VERSION 5.8 ;
BUSBITCHARS "[]" ;
DIVIDERCHAR "/" ;
UNITS
    DATABASE MICRONS 1000 ;
END UNITS

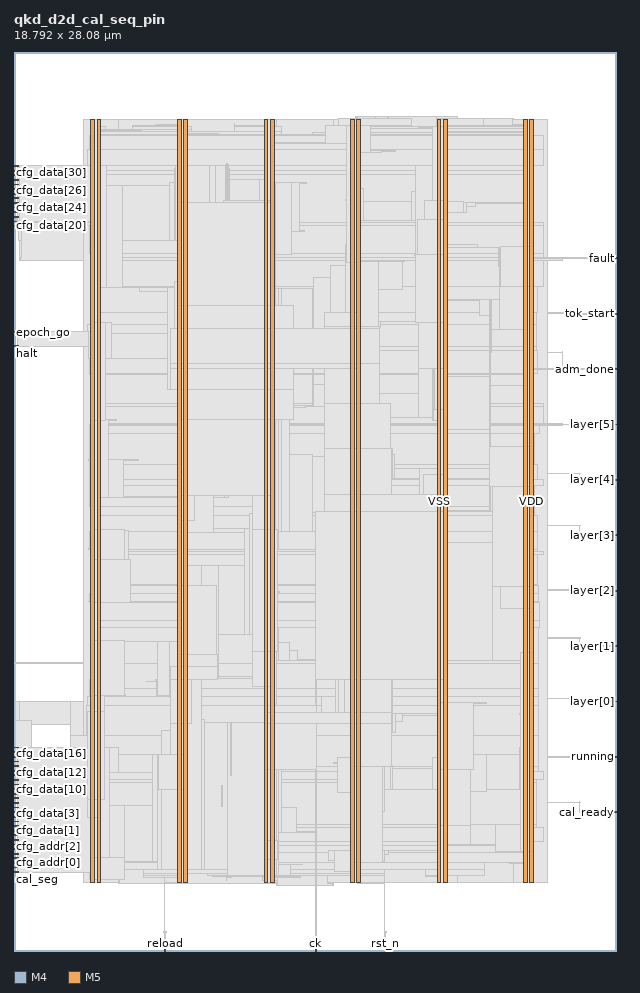
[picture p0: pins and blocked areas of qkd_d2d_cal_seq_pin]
MACRO qkd_d2d_cal_seq_pin
  FOREIGN qkd_d2d_cal_seq_pin 0 0 ;
  CLASS BLOCK ;
  SIZE 18.792 BY 28.08 ;
  PIN adm_done
    DIRECTION OUTPUT ;
    USE SIGNAL ;
    PORT
      LAYER M4 ;
        RECT  18.648 18.144 18.792 18.168 ;
    END
  END adm_done
  PIN cal_ready
    DIRECTION OUTPUT ;
    USE SIGNAL ;
    PORT
      LAYER M4 ;
        RECT  18.648 4.32 18.792 4.344 ;
    END
  END cal_ready
  PIN cal_seg
    DIRECTION OUTPUT ;
    USE SIGNAL ;
    PORT
      LAYER M4 ;
        RECT  0 2.448 0.144 2.472 ;
    END
  END cal_seg
  PIN cal_start
    DIRECTION OUTPUT ;
    USE SIGNAL ;
    PORT
      LAYER M4 ;
        RECT  0 2.592 0.144 2.616 ;
    END
  END cal_start
  PIN cfg_addr[0]
    DIRECTION OUTPUT ;
    USE SIGNAL ;
    PORT
      LAYER M4 ;
        RECT  0 2.736 0.144 2.76 ;
    END
  END cfg_addr[0]
  PIN cfg_addr[1]
    DIRECTION OUTPUT ;
    USE SIGNAL ;
    PORT
      LAYER M4 ;
        RECT  0 2.88 0.144 2.904 ;
    END
  END cfg_addr[1]
  PIN cfg_addr[2]
    DIRECTION OUTPUT ;
    USE SIGNAL ;
    PORT
      LAYER M4 ;
        RECT  0 3.024 0.144 3.048 ;
    END
  END cfg_addr[2]
  PIN cfg_addr[3]
    DIRECTION OUTPUT ;
    USE SIGNAL ;
    PORT
      LAYER M4 ;
        RECT  0 3.168 0.144 3.192 ;
    END
  END cfg_addr[3]
  PIN cfg_addr[4]
    DIRECTION OUTPUT ;
    USE SIGNAL ;
    PORT
      LAYER M4 ;
        RECT  0 3.312 0.144 3.336 ;
    END
  END cfg_addr[4]
  PIN cfg_addr[5]
    DIRECTION OUTPUT ;
    USE SIGNAL ;
    PORT
      LAYER M4 ;
        RECT  0 3.456 0.144 3.48 ;
    END
  END cfg_addr[5]
  PIN cfg_data[0]
    DIRECTION OUTPUT ;
    USE SIGNAL ;
    PORT
      LAYER M4 ;
        RECT  0 3.6 0.144 3.624 ;
    END
  END cfg_data[0]
  PIN cfg_data[10]
    DIRECTION OUTPUT ;
    USE SIGNAL ;
    PORT
      LAYER M4 ;
        RECT  0 5.04 0.144 5.064 ;
    END
  END cfg_data[10]
  PIN cfg_data[11]
    DIRECTION OUTPUT ;
    USE SIGNAL ;
    PORT
      LAYER M4 ;
        RECT  0 5.184 0.144 5.208 ;
    END
  END cfg_data[11]
  PIN cfg_data[12]
    DIRECTION OUTPUT ;
    USE SIGNAL ;
    PORT
      LAYER M4 ;
        RECT  0 5.328 0.144 5.352 ;
    END
  END cfg_data[12]
  PIN cfg_data[13]
    DIRECTION OUTPUT ;
    USE SIGNAL ;
    PORT
      LAYER M4 ;
        RECT  0 5.472 0.144 5.496 ;
    END
  END cfg_data[13]
  PIN cfg_data[14]
    DIRECTION OUTPUT ;
    USE SIGNAL ;
    PORT
      LAYER M4 ;
        RECT  0 5.616 0.144 5.64 ;
    END
  END cfg_data[14]
  PIN cfg_data[15]
    DIRECTION OUTPUT ;
    USE SIGNAL ;
    PORT
      LAYER M4 ;
        RECT  0 5.76 0.144 5.784 ;
    END
  END cfg_data[15]
  PIN cfg_data[16]
    DIRECTION OUTPUT ;
    USE SIGNAL ;
    PORT
      LAYER M4 ;
        RECT  0 5.904 0.144 5.928 ;
    END
  END cfg_data[16]
  PIN cfg_data[17]
    DIRECTION OUTPUT ;
    USE SIGNAL ;
    PORT
      LAYER M4 ;
        RECT  0 6.048 0.144 6.072 ;
    END
  END cfg_data[17]
  PIN cfg_data[18]
    DIRECTION OUTPUT ;
    USE SIGNAL ;
    PORT
      LAYER M4 ;
        RECT  0 6.192 0.144 6.216 ;
    END
  END cfg_data[18]
  PIN cfg_data[19]
    DIRECTION OUTPUT ;
    USE SIGNAL ;
    PORT
      LAYER M4 ;
        RECT  0 6.336 0.144 6.36 ;
    END
  END cfg_data[19]
  PIN cfg_data[1]
    DIRECTION OUTPUT ;
    USE SIGNAL ;
    PORT
      LAYER M4 ;
        RECT  0 3.744 0.144 3.768 ;
    END
  END cfg_data[1]
  PIN cfg_data[20]
    DIRECTION OUTPUT ;
    USE SIGNAL ;
    PORT
      LAYER M4 ;
        RECT  0 22.608 0.144 22.632 ;
    END
  END cfg_data[20]
  PIN cfg_data[21]
    DIRECTION OUTPUT ;
    USE SIGNAL ;
    PORT
      LAYER M4 ;
        RECT  0 22.752 0.144 22.776 ;
    END
  END cfg_data[21]
  PIN cfg_data[22]
    DIRECTION OUTPUT ;
    USE SIGNAL ;
    PORT
      LAYER M4 ;
        RECT  0 22.896 0.144 22.92 ;
    END
  END cfg_data[22]
  PIN cfg_data[23]
    DIRECTION OUTPUT ;
    USE SIGNAL ;
    PORT
      LAYER M4 ;
        RECT  0 23.04 0.144 23.064 ;
    END
  END cfg_data[23]
  PIN cfg_data[24]
    DIRECTION OUTPUT ;
    USE SIGNAL ;
    PORT
      LAYER M4 ;
        RECT  0 23.184 0.144 23.208 ;
    END
  END cfg_data[24]
  PIN cfg_data[25]
    DIRECTION OUTPUT ;
    USE SIGNAL ;
    PORT
      LAYER M4 ;
        RECT  0 23.328 0.144 23.352 ;
    END
  END cfg_data[25]
  PIN cfg_data[26]
    DIRECTION OUTPUT ;
    USE SIGNAL ;
    PORT
      LAYER M4 ;
        RECT  0 23.472 0.144 23.496 ;
    END
  END cfg_data[26]
  PIN cfg_data[27]
    DIRECTION OUTPUT ;
    USE SIGNAL ;
    PORT
      LAYER M4 ;
        RECT  0 23.616 0.144 23.64 ;
    END
  END cfg_data[27]
  PIN cfg_data[28]
    DIRECTION OUTPUT ;
    USE SIGNAL ;
    PORT
      LAYER M4 ;
        RECT  0 23.76 0.144 23.784 ;
    END
  END cfg_data[28]
  PIN cfg_data[29]
    DIRECTION OUTPUT ;
    USE SIGNAL ;
    PORT
      LAYER M4 ;
        RECT  0 23.904 0.144 23.928 ;
    END
  END cfg_data[29]
  PIN cfg_data[2]
    DIRECTION OUTPUT ;
    USE SIGNAL ;
    PORT
      LAYER M4 ;
        RECT  0 3.888 0.144 3.912 ;
    END
  END cfg_data[2]
  PIN cfg_data[30]
    DIRECTION OUTPUT ;
    USE SIGNAL ;
    PORT
      LAYER M4 ;
        RECT  0 24.048 0.144 24.072 ;
    END
  END cfg_data[30]
  PIN cfg_data[31]
    DIRECTION OUTPUT ;
    USE SIGNAL ;
    PORT
      LAYER M4 ;
        RECT  0 24.192 0.144 24.216 ;
    END
  END cfg_data[31]
  PIN cfg_data[3]
    DIRECTION OUTPUT ;
    USE SIGNAL ;
    PORT
      LAYER M4 ;
        RECT  0 4.032 0.144 4.056 ;
    END
  END cfg_data[3]
  PIN cfg_data[4]
    DIRECTION OUTPUT ;
    USE SIGNAL ;
    PORT
      LAYER M4 ;
        RECT  0 4.176 0.144 4.2 ;
    END
  END cfg_data[4]
  PIN cfg_data[5]
    DIRECTION OUTPUT ;
    USE SIGNAL ;
    PORT
      LAYER M4 ;
        RECT  0 4.32 0.144 4.344 ;
    END
  END cfg_data[5]
  PIN cfg_data[6]
    DIRECTION OUTPUT ;
    USE SIGNAL ;
    PORT
      LAYER M4 ;
        RECT  0 4.464 0.144 4.488 ;
    END
  END cfg_data[6]
  PIN cfg_data[7]
    DIRECTION OUTPUT ;
    USE SIGNAL ;
    PORT
      LAYER M4 ;
        RECT  0 4.608 0.144 4.632 ;
    END
  END cfg_data[7]
  PIN cfg_data[8]
    DIRECTION OUTPUT ;
    USE SIGNAL ;
    PORT
      LAYER M4 ;
        RECT  0 4.752 0.144 4.776 ;
    END
  END cfg_data[8]
  PIN cfg_data[9]
    DIRECTION OUTPUT ;
    USE SIGNAL ;
    PORT
      LAYER M4 ;
        RECT  0 4.896 0.144 4.92 ;
    END
  END cfg_data[9]
  PIN cfg_rx_we
    DIRECTION OUTPUT ;
    USE SIGNAL ;
    PORT
      LAYER M4 ;
        RECT  0 24.336 0.144 24.36 ;
    END
  END cfg_rx_we
  PIN cfg_tx_we
    DIRECTION OUTPUT ;
    USE SIGNAL ;
    PORT
      LAYER M4 ;
        RECT  0 24.48 0.144 24.504 ;
    END
  END cfg_tx_we
  PIN ck
    DIRECTION INPUT ;
    USE SIGNAL ;
    PORT
      LAYER M5 ;
        RECT  9.408 0 9.432 0.144 ;
    END
  END ck
  PIN epoch_go
    DIRECTION INPUT ;
    USE SIGNAL ;
    PORT
      LAYER M4 ;
        RECT  0 19.296 0.144 19.32 ;
    END
  END epoch_go
  PIN fault
    DIRECTION OUTPUT ;
    USE SIGNAL ;
    PORT
      LAYER M4 ;
        RECT  18.648 21.6 18.792 21.624 ;
    END
  END fault
  PIN halt
    DIRECTION INPUT ;
    USE SIGNAL ;
    PORT
      LAYER M4 ;
        RECT  0 18.864 0.144 18.888 ;
    END
  END halt
  PIN layer[0]
    DIRECTION OUTPUT ;
    USE SIGNAL ;
    PORT
      LAYER M4 ;
        RECT  18.648 7.776 18.792 7.8 ;
    END
  END layer[0]
  PIN layer[1]
    DIRECTION OUTPUT ;
    USE SIGNAL ;
    PORT
      LAYER M4 ;
        RECT  18.648 9.504 18.792 9.528 ;
    END
  END layer[1]
  PIN layer[2]
    DIRECTION OUTPUT ;
    USE SIGNAL ;
    PORT
      LAYER M4 ;
        RECT  18.648 11.232 18.792 11.256 ;
    END
  END layer[2]
  PIN layer[3]
    DIRECTION OUTPUT ;
    USE SIGNAL ;
    PORT
      LAYER M4 ;
        RECT  18.648 12.96 18.792 12.984 ;
    END
  END layer[3]
  PIN layer[4]
    DIRECTION OUTPUT ;
    USE SIGNAL ;
    PORT
      LAYER M4 ;
        RECT  18.648 14.688 18.792 14.712 ;
    END
  END layer[4]
  PIN layer[5]
    DIRECTION OUTPUT ;
    USE SIGNAL ;
    PORT
      LAYER M4 ;
        RECT  18.648 16.416 18.792 16.44 ;
    END
  END layer[5]
  PIN reload
    DIRECTION INPUT ;
    USE SIGNAL ;
    PORT
      LAYER M5 ;
        RECT  4.704 0 4.728 0.144 ;
    END
  END reload
  PIN rst_n
    DIRECTION INPUT ;
    USE SIGNAL ;
    PORT
      LAYER M5 ;
        RECT  11.568 0 11.592 0.144 ;
    END
  END rst_n
  PIN running
    DIRECTION OUTPUT ;
    USE SIGNAL ;
    PORT
      LAYER M4 ;
        RECT  18.648 6.048 18.792 6.072 ;
    END
  END running
  PIN tok_start
    DIRECTION OUTPUT ;
    USE SIGNAL ;
    PORT
      LAYER M4 ;
        RECT  18.648 19.872 18.792 19.896 ;
    END
  END tok_start
  PIN VDD
    DIRECTION INOUT ;
    USE POWER ;
    PORT
      LAYER M5 ;
        RECT  16.092 2.151 16.212 25.929 ;
        RECT  13.392 2.151 13.512 25.929 ;
        RECT  10.692 2.151 10.812 25.929 ;
        RECT  7.992 2.151 8.112 25.929 ;
        RECT  5.292 2.151 5.412 25.929 ;
        RECT  2.592 2.151 2.712 25.929 ;
    END
  END VDD
  PIN VSS
    DIRECTION INOUT ;
    USE GROUND ;
    PORT
      LAYER M5 ;
        RECT  15.9 2.137 16.02 25.943 ;
        RECT  13.2 2.137 13.32 25.943 ;
        RECT  10.5 2.137 10.62 25.943 ;
        RECT  7.8 2.137 7.92 25.943 ;
        RECT  5.1 2.137 5.22 25.943 ;
        RECT  2.4 2.137 2.52 25.943 ;
    END
  END VSS
  OBS
    LAYER RVTN ;
     RECT  2.16 2.16 16.632 2.295 ;
     RECT  2.16 2.565 16.632 2.835 ;
     RECT  2.16 3.105 16.632 3.375 ;
     RECT  2.16 3.645 16.632 3.915 ;
     RECT  2.16 4.185 16.632 4.455 ;
     RECT  2.16 4.725 16.632 4.995 ;
     RECT  2.16 5.265 16.632 5.535 ;
     RECT  2.16 5.805 16.632 6.075 ;
     RECT  2.16 6.345 16.632 6.615 ;
     RECT  2.16 6.885 16.632 7.155 ;
     RECT  2.16 7.425 16.632 7.695 ;
     RECT  2.16 7.965 16.632 8.235 ;
     RECT  2.16 8.505 16.632 8.775 ;
     RECT  2.16 9.045 16.632 9.315 ;
     RECT  2.16 9.585 16.632 9.855 ;
     RECT  2.16 10.125 16.632 10.395 ;
     RECT  2.16 10.665 16.632 10.935 ;
     RECT  2.16 11.205 16.632 11.475 ;
     RECT  2.16 11.745 16.632 12.015 ;
     RECT  2.16 12.285 16.632 12.555 ;
     RECT  2.16 12.825 16.632 13.095 ;
     RECT  2.16 13.365 16.632 13.635 ;
     RECT  2.16 13.905 16.632 14.175 ;
     RECT  2.16 14.445 16.632 14.715 ;
     RECT  2.16 14.985 16.632 15.255 ;
     RECT  2.16 15.525 16.632 15.795 ;
     RECT  2.16 16.065 16.632 16.335 ;
     RECT  2.16 16.605 16.632 16.875 ;
     RECT  2.16 17.145 16.632 17.415 ;
     RECT  2.16 17.685 16.632 17.955 ;
     RECT  2.16 18.225 16.632 18.495 ;
     RECT  2.16 18.765 16.632 19.035 ;
     RECT  2.16 19.305 16.632 19.575 ;
     RECT  2.16 19.845 16.632 20.115 ;
     RECT  2.16 20.385 16.632 20.655 ;
     RECT  2.16 20.925 16.632 21.195 ;
     RECT  2.16 21.465 16.632 21.735 ;
     RECT  2.16 22.005 16.632 22.275 ;
     RECT  2.16 22.545 16.632 22.815 ;
     RECT  2.16 23.085 16.632 23.355 ;
     RECT  2.16 23.625 16.632 23.895 ;
     RECT  2.16 24.165 16.632 24.435 ;
     RECT  2.16 24.705 16.632 24.975 ;
     RECT  2.16 25.245 16.632 25.515 ;
     RECT  2.16 25.785 16.632 25.92 ;
    LAYER RVTP ;
     RECT  2.16 2.295 16.632 2.565 ;
     RECT  2.16 2.835 16.632 3.105 ;
     RECT  2.16 3.375 16.632 3.645 ;
     RECT  2.16 3.915 16.632 4.185 ;
     RECT  2.16 4.455 16.632 4.725 ;
     RECT  2.16 4.995 16.632 5.265 ;
     RECT  2.16 5.535 16.632 5.805 ;
     RECT  2.16 6.075 16.632 6.345 ;
     RECT  2.16 6.615 16.632 6.885 ;
     RECT  2.16 7.155 16.632 7.425 ;
     RECT  2.16 7.695 16.632 7.965 ;
     RECT  2.16 8.235 16.632 8.505 ;
     RECT  2.16 8.775 16.632 9.045 ;
     RECT  2.16 9.315 16.632 9.585 ;
     RECT  2.16 9.855 16.632 10.125 ;
     RECT  2.16 10.395 16.632 10.665 ;
     RECT  2.16 10.935 16.632 11.205 ;
     RECT  2.16 11.475 16.632 11.745 ;
     RECT  2.16 12.015 16.632 12.285 ;
     RECT  2.16 12.555 16.632 12.825 ;
     RECT  2.16 13.095 16.632 13.365 ;
     RECT  2.16 13.635 16.632 13.905 ;
     RECT  2.16 14.175 16.632 14.445 ;
     RECT  2.16 14.715 16.632 14.985 ;
     RECT  2.16 15.255 16.632 15.525 ;
     RECT  2.16 15.795 16.632 16.065 ;
     RECT  2.16 16.335 16.632 16.605 ;
     RECT  2.16 16.875 16.632 17.145 ;
     RECT  2.16 17.415 16.632 17.685 ;
     RECT  2.16 17.955 16.632 18.225 ;
     RECT  2.16 18.495 16.632 18.765 ;
     RECT  2.16 19.035 16.632 19.305 ;
     RECT  2.16 19.575 16.632 19.845 ;
     RECT  2.16 20.115 16.632 20.385 ;
     RECT  2.16 20.655 16.632 20.925 ;
     RECT  2.16 21.195 16.632 21.465 ;
     RECT  2.16 21.735 16.632 22.005 ;
     RECT  2.16 22.275 16.632 22.545 ;
     RECT  2.16 22.815 16.632 23.085 ;
     RECT  2.16 23.355 16.632 23.625 ;
     RECT  2.16 23.895 16.632 24.165 ;
     RECT  2.16 24.435 16.632 24.705 ;
     RECT  2.16 24.975 16.632 25.245 ;
     RECT  2.16 25.515 16.632 25.785 ;
    LAYER M1 ;
     RECT  2.16 2.151 16.632 25.929 ;
    LAYER M2 ;
     RECT  0.067 22.716 0.139 22.842 ;
     RECT  0.031 5.121 0.167 5.139 ;
     RECT  0.139 22.176 0.167 22.842 ;
     RECT  0.139 7.776 0.175 7.794 ;
     RECT  0.167 22.176 0.175 22.734 ;
     RECT  0.139 2.646 0.535 2.664 ;
     RECT  0.175 7.056 1.759 7.794 ;
     RECT  0.535 2.646 2.16 2.754 ;
     RECT  1.759 6.696 2.16 7.794 ;
     RECT  0.031 8.982 2.16 9 ;
     RECT  0.175 21.546 2.16 22.734 ;
     RECT  2.16 2.151 3.271 25.929 ;
     RECT  3.271 2.106 8.203 25.929 ;
     RECT  8.203 2.034 9.959 25.929 ;
     RECT  9.959 2.151 10.111 25.929 ;
     RECT  10.111 2.151 10.651 25.974 ;
     RECT  10.651 2.151 10.723 26.046 ;
     RECT  10.723 2.106 11.291 26.046 ;
     RECT  11.291 2.151 13.847 26.046 ;
     RECT  13.847 2.151 15.575 25.974 ;
     RECT  15.575 2.151 16.632 25.929 ;
     RECT  16.632 16.416 17.123 16.434 ;
     RECT  16.632 18.666 17.123 18.684 ;
     RECT  16.632 21.546 17.123 21.564 ;
     RECT  16.632 4.626 17.663 4.644 ;
     RECT  16.632 6.048 17.663 6.066 ;
     RECT  16.632 7.866 17.663 7.884 ;
     RECT  16.632 9.756 17.663 9.774 ;
     RECT  16.632 11.25 17.663 11.268 ;
     RECT  16.632 13.266 17.663 13.284 ;
     RECT  16.632 14.886 17.663 14.904 ;
     RECT  16.632 19.89 17.663 19.908 ;
    LAYER M3 ;
     RECT  9.936 2.029 9.954 2.101 ;
     RECT  11.556 0.571 11.574 2.101 ;
     RECT  4.68 0.571 4.698 2.143 ;
     RECT  8.208 2.029 8.226 2.143 ;
     RECT  9.792 2.101 9.954 2.143 ;
     RECT  10.728 2.101 11.574 2.143 ;
     RECT  7.815 2.143 8.226 2.191 ;
     RECT  2.415 2.143 2.505 2.227 ;
     RECT  2.34 2.227 2.505 2.251 ;
     RECT  3.276 2.101 3.294 2.251 ;
     RECT  4.68 2.143 5.205 2.299 ;
     RECT  6.624 2.191 6.642 2.299 ;
     RECT  7.74 2.191 8.226 2.299 ;
     RECT  6.624 2.299 6.786 2.335 ;
     RECT  7.74 2.299 8.946 2.335 ;
     RECT  13.215 2.143 13.305 2.335 ;
     RECT  4.032 2.299 5.205 2.371 ;
     RECT  6.192 2.335 8.946 2.371 ;
     RECT  9.792 2.143 11.574 2.371 ;
     RECT  12.852 2.335 13.305 2.371 ;
     RECT  4.032 2.371 5.274 2.413 ;
     RECT  6.048 2.371 11.574 2.413 ;
     RECT  15.915 2.143 16.005 2.413 ;
     RECT  2.34 2.251 3.294 2.443 ;
     RECT  2.304 2.443 3.294 2.533 ;
     RECT  4.032 2.413 11.574 2.533 ;
     RECT  12.852 2.371 14.67 2.533 ;
     RECT  0.144 2.641 0.162 2.731 ;
     RECT  15.915 2.413 16.197 2.731 ;
     RECT  2.304 2.533 14.67 2.767 ;
     RECT  15.444 2.731 16.197 2.767 ;
     RECT  0.144 2.731 0.558 2.909 ;
     RECT  0.144 2.909 0.162 3.053 ;
     RECT  2.304 2.767 16.197 3.073 ;
     RECT  2.268 3.073 16.197 3.299 ;
     RECT  2.304 3.299 16.197 3.415 ;
     RECT  2.304 3.415 16.506 3.839 ;
     RECT  2.304 3.839 16.29 3.947 ;
     RECT  0.216 4.027 0.234 4.445 ;
     RECT  17.64 4.315 17.658 4.649 ;
     RECT  0.18 4.603 0.198 4.891 ;
     RECT  0.144 4.891 0.198 5.116 ;
     RECT  2.34 3.947 16.29 5.269 ;
     RECT  0.036 5.116 0.198 5.323 ;
     RECT  2.304 5.269 16.29 5.341 ;
     RECT  2.304 5.341 16.506 5.603 ;
     RECT  2.304 5.603 16.362 5.755 ;
     RECT  0.036 5.323 0.378 6.043 ;
     RECT  17.64 6.043 17.658 6.08 ;
     RECT  1.764 5.755 16.362 6.719 ;
     RECT  0.036 6.043 0.558 7.187 ;
     RECT  2.268 6.719 16.362 7.655 ;
     RECT  0.036 7.187 0.162 7.799 ;
     RECT  17.64 7.771 17.658 7.889 ;
     RECT  2.304 7.655 16.362 7.925 ;
     RECT  2.34 7.925 16.362 8.195 ;
     RECT  2.34 8.195 2.697 8.465 ;
     RECT  2.415 8.465 2.697 8.971 ;
     RECT  3.42 8.195 16.362 8.971 ;
     RECT  0.036 7.799 0.054 9.005 ;
     RECT  17.64 9.499 17.658 9.779 ;
     RECT  2.415 8.971 16.362 10.093 ;
     RECT  2.415 10.093 16.398 10.327 ;
     RECT  2.376 10.327 16.398 10.859 ;
     RECT  2.376 10.859 16.362 10.891 ;
     RECT  2.34 10.891 16.362 11.165 ;
     RECT  17.64 11.227 17.658 11.273 ;
     RECT  2.376 11.165 16.362 11.399 ;
     RECT  2.376 11.399 16.326 11.435 ;
     RECT  2.415 11.435 16.326 12.361 ;
     RECT  2.415 12.361 16.506 12.479 ;
     RECT  2.415 12.479 16.326 12.523 ;
     RECT  2.34 12.523 16.326 13.091 ;
     RECT  17.64 12.955 17.658 13.289 ;
     RECT  2.376 13.091 16.326 13.595 ;
     RECT  2.376 13.595 16.254 13.873 ;
     RECT  2.34 13.873 16.254 14.521 ;
     RECT  2.34 14.521 16.506 14.711 ;
     RECT  17.64 14.683 17.658 14.909 ;
     RECT  2.34 14.711 16.326 15.179 ;
     RECT  2.34 15.179 16.254 16.141 ;
     RECT  2.34 16.141 16.398 16.405 ;
     RECT  2.34 16.405 17.118 16.439 ;
     RECT  2.376 16.439 17.118 16.445 ;
     RECT  2.376 16.445 16.506 16.979 ;
     RECT  2.415 16.979 16.506 17.069 ;
     RECT  2.415 17.069 16.197 17.995 ;
     RECT  2.34 17.995 16.197 18.031 ;
     RECT  17.1 18.139 17.118 18.689 ;
     RECT  2.34 18.031 16.326 18.725 ;
     RECT  2.34 18.725 16.29 18.859 ;
     RECT  2.304 18.859 16.29 19.535 ;
     RECT  17.64 19.867 17.658 19.913 ;
     RECT  2.415 19.535 16.29 19.921 ;
     RECT  2.415 19.921 16.326 20.731 ;
     RECT  2.415 20.731 16.506 21.541 ;
     RECT  2.415 21.541 17.118 21.629 ;
     RECT  0.18 21.541 0.198 21.631 ;
     RECT  2.415 21.629 16.506 21.775 ;
     RECT  0.18 21.631 0.234 22.171 ;
     RECT  0.144 22.171 0.234 22.549 ;
     RECT  2.34 21.775 16.506 22.621 ;
     RECT  0.144 22.549 0.27 22.711 ;
     RECT  2.304 22.621 16.506 22.739 ;
     RECT  0.072 22.711 0.27 22.847 ;
     RECT  0.144 22.847 0.27 23.083 ;
     RECT  0.144 23.083 0.306 23.213 ;
     RECT  0.144 23.213 0.27 23.357 ;
     RECT  0.144 23.357 0.234 23.885 ;
     RECT  0.144 23.885 0.162 24.077 ;
     RECT  2.304 22.739 16.197 24.241 ;
     RECT  2.268 24.241 16.197 24.365 ;
     RECT  2.304 24.365 16.197 24.511 ;
     RECT  2.304 24.511 16.506 25.007 ;
     RECT  2.34 25.007 16.506 25.439 ;
     RECT  2.415 25.439 16.197 25.475 ;
     RECT  9.324 25.475 16.197 25.547 ;
     RECT  2.415 25.475 8.334 25.583 ;
     RECT  2.415 25.583 5.526 25.619 ;
     RECT  9.72 25.547 16.197 25.667 ;
     RECT  2.415 25.619 2.862 25.709 ;
     RECT  3.708 25.619 5.526 25.709 ;
     RECT  6.876 25.583 8.334 25.709 ;
     RECT  9.72 25.667 16.074 25.715 ;
     RECT  3.708 25.709 5.205 25.745 ;
     RECT  6.876 25.709 7.905 25.745 ;
     RECT  13.176 25.715 16.074 25.745 ;
     RECT  9.72 25.715 12.402 25.757 ;
     RECT  4.428 25.745 5.205 25.781 ;
     RECT  15.552 25.745 16.074 25.781 ;
     RECT  6.876 25.745 6.894 25.817 ;
     RECT  2.415 25.709 2.682 25.889 ;
     RECT  2.415 25.889 2.505 25.937 ;
     RECT  5.115 25.781 5.205 25.937 ;
     RECT  7.815 25.745 7.905 25.937 ;
     RECT  15.552 25.781 16.005 25.937 ;
     RECT  10.116 25.757 12.402 25.979 ;
     RECT  13.176 25.745 14.634 25.979 ;
     RECT  15.552 25.937 15.57 25.979 ;
     RECT  10.656 25.979 10.674 26.051 ;
     RECT  11.664 25.979 11.682 26.051 ;
     RECT  13.176 25.979 13.842 26.051 ;
    LAYER M4 ;
     RECT  0.108 22.608 0.173 24.504 ;
     RECT  0.108 18.864 2.329 19.32 ;
     RECT  0.108 2.448 2.408 6.36 ;
     RECT  2.293 7.44 2.408 7.464 ;
     RECT  2.329 10.896 2.408 10.92 ;
     RECT  2.329 12.528 2.408 12.552 ;
     RECT  2.329 15.312 2.408 15.336 ;
     RECT  2.401 16.56 2.408 16.584 ;
     RECT  2.329 18.48 2.408 19.32 ;
     RECT  0.173 22.752 2.408 24.504 ;
     RECT  2.408 2.148 2.512 25.932 ;
     RECT  2.512 2.256 2.704 25.662 ;
     RECT  2.704 20.688 2.873 24.504 ;
     RECT  2.704 14.16 2.945 16.584 ;
     RECT  2.704 2.256 2.981 6.36 ;
     RECT  2.704 18.48 3.053 19.608 ;
     RECT  2.945 16.56 3.197 16.584 ;
     RECT  2.981 5.568 3.269 6.36 ;
     RECT  2.873 20.688 3.377 23.88 ;
     RECT  2.945 14.16 3.413 15.336 ;
     RECT  2.981 2.256 3.443 4.536 ;
     RECT  2.704 8.976 3.443 9.672 ;
     RECT  2.704 7.968 3.485 7.992 ;
     RECT  2.704 12.192 3.557 13.128 ;
     RECT  3.557 12.192 3.635 12.216 ;
     RECT  2.704 10.896 3.657 10.92 ;
     RECT  3.413 15.312 3.881 15.336 ;
     RECT  3.377 20.688 3.913 20.712 ;
     RECT  2.704 25.584 3.989 25.608 ;
     RECT  3.443 2.784 4.309 4.536 ;
     RECT  3.269 5.568 4.309 6.12 ;
     RECT  4.129 8.4 4.417 8.424 ;
     RECT  4.417 8.4 4.453 8.472 ;
     RECT  4.309 2.784 4.489 6.12 ;
     RECT  4.453 7.968 4.489 8.472 ;
     RECT  3.443 9.648 4.489 9.672 ;
     RECT  4.489 2.544 4.597 6.12 ;
     RECT  4.669 0.576 4.753 0.6 ;
     RECT  3.053 18.48 4.777 19.272 ;
     RECT  3.913 20.592 4.777 20.712 ;
     RECT  4.489 7.968 4.844 9.672 ;
     RECT  3.377 22.176 4.849 23.88 ;
     RECT  4.777 17.52 4.993 20.712 ;
     RECT  4.849 22.176 4.993 23.976 ;
     RECT  4.993 22.176 5.029 24.408 ;
     RECT  4.844 7.92 5.101 9.672 ;
     RECT  4.597 2.544 5.108 6.888 ;
     RECT  5.101 7.92 5.108 9.816 ;
     RECT  3.413 14.16 5.108 14.184 ;
     RECT  4.993 17.52 5.108 20.904 ;
     RECT  5.029 22.176 5.108 24.504 ;
     RECT  5.108 2.148 5.212 25.932 ;
     RECT  5.212 2.418 5.404 25.662 ;
     RECT  5.404 2.544 5.861 12.024 ;
     RECT  5.861 2.544 5.933 7.224 ;
     RECT  5.404 17.616 6.113 24.504 ;
     RECT  5.404 13.056 6.221 16.056 ;
     RECT  6.113 17.808 6.275 24.504 ;
     RECT  5.404 25.488 6.365 25.512 ;
     RECT  5.861 8.496 6.371 12.024 ;
     RECT  6.221 14.16 6.572 16.056 ;
     RECT  6.275 22.8 6.613 24.504 ;
     RECT  5.933 2.544 6.649 7.128 ;
     RECT  6.572 14.16 6.689 16.44 ;
     RECT  6.613 22.8 6.697 24.552 ;
     RECT  6.697 22.8 6.725 24.408 ;
     RECT  6.371 9.888 7.189 12.024 ;
     RECT  6.221 13.056 7.189 13.176 ;
     RECT  6.275 17.808 7.189 20.328 ;
     RECT  6.689 14.736 7.297 16.44 ;
     RECT  7.189 17.712 7.297 20.328 ;
     RECT  7.189 9.888 7.333 13.176 ;
     RECT  6.371 8.496 7.429 8.568 ;
     RECT  6.275 21.744 7.621 21.768 ;
     RECT  7.621 21.504 7.657 21.768 ;
     RECT  6.725 22.8 7.657 24.072 ;
     RECT  6.649 2.352 7.808 7.128 ;
     RECT  7.429 8.256 7.808 8.568 ;
     RECT  7.333 9.888 7.808 13.656 ;
     RECT  7.297 14.736 7.808 20.328 ;
     RECT  7.657 21.504 7.808 24.072 ;
     RECT  7.808 2.148 7.912 25.932 ;
     RECT  7.912 2.352 8.104 25.662 ;
     RECT  8.104 12.528 8.165 23.976 ;
     RECT  8.104 2.352 8.201 10.104 ;
     RECT  8.201 2.352 8.243 7.656 ;
     RECT  8.201 9.072 8.243 10.104 ;
     RECT  8.165 12.528 8.243 20.664 ;
     RECT  8.104 11.184 8.284 11.208 ;
     RECT  8.243 3.696 8.345 7.656 ;
     RECT  8.243 13.104 8.345 20.664 ;
     RECT  8.345 5.664 8.531 7.656 ;
     RECT  8.243 9.072 8.597 9.624 ;
     RECT  8.345 13.104 8.597 17.016 ;
     RECT  8.243 2.352 8.633 2.712 ;
     RECT  8.165 21.744 8.669 23.976 ;
     RECT  8.597 16.608 8.723 17.016 ;
     RECT  8.345 3.696 8.813 4.488 ;
     RECT  8.597 9.072 8.849 9.384 ;
     RECT  8.669 22.464 8.921 23.976 ;
     RECT  8.531 6.576 8.957 7.224 ;
     RECT  8.633 2.688 8.993 2.712 ;
     RECT  8.921 22.464 9.065 22.488 ;
     RECT  8.723 16.944 9.101 17.016 ;
     RECT  8.921 23.952 9.137 23.976 ;
     RECT  8.957 6.912 9.245 7.224 ;
     RECT  9.101 16.992 9.313 17.016 ;
     RECT  8.345 18.192 9.313 20.664 ;
     RECT  8.597 13.104 9.317 15.48 ;
     RECT  9.313 16.992 9.349 20.664 ;
     RECT  9.349 16.992 9.353 21 ;
     RECT  8.813 3.696 9.425 3.72 ;
     RECT  9.245 7.104 9.601 7.224 ;
     RECT  8.104 25.2 9.709 25.224 ;
     RECT  9.353 19.056 9.889 21 ;
     RECT  9.817 2.832 9.997 3.144 ;
     RECT  8.849 9.072 10.021 9.096 ;
     RECT  9.624 10.752 10.021 10.776 ;
     RECT  9.601 7.104 10.033 7.944 ;
     RECT  10.021 8.976 10.033 9.096 ;
     RECT  9.961 5.856 10.105 5.88 ;
     RECT  10.033 7.104 10.117 9.096 ;
     RECT  10.021 10.272 10.117 10.776 ;
     RECT  10.117 7.104 10.309 11.016 ;
     RECT  9.644 12.288 10.309 12.312 ;
     RECT  9.317 13.68 10.357 15.432 ;
     RECT  9.353 16.992 10.357 17.688 ;
     RECT  9.889 19.056 10.357 21.384 ;
     RECT  10.357 23.424 10.501 23.448 ;
     RECT  9.997 2.496 10.508 3.144 ;
     RECT  10.105 4.944 10.508 6.024 ;
     RECT  10.309 7.104 10.508 12.312 ;
     RECT  10.357 13.584 10.508 17.688 ;
     RECT  10.357 19.056 10.508 22.056 ;
     RECT  10.501 23.328 10.508 23.448 ;
     RECT  9.709 25.2 10.508 25.752 ;
     RECT  10.508 2.148 10.612 25.932 ;
     RECT  10.612 2.418 10.804 25.752 ;
     RECT  10.804 22.8 10.901 23.784 ;
     RECT  10.804 24.912 11.117 25.752 ;
     RECT  10.804 19.44 11.369 21.528 ;
     RECT  10.804 16.656 11.411 18.36 ;
     RECT  10.804 4.368 11.441 15.672 ;
     RECT  11.369 19.44 11.441 19.656 ;
     RECT  11.117 24.912 11.477 24.984 ;
     RECT  10.804 2.784 11.549 3.144 ;
     RECT  11.441 4.368 11.549 13.08 ;
     RECT  11.545 0.576 11.629 0.6 ;
     RECT  11.549 3.024 11.693 3.144 ;
     RECT  11.549 5.04 11.74 13.08 ;
     RECT  11.74 5.04 11.795 5.784 ;
     RECT  11.441 14.736 11.795 15.672 ;
     RECT  11.74 6.816 11.801 13.08 ;
     RECT  11.795 14.736 11.873 15.48 ;
     RECT  11.801 6.816 11.909 7.416 ;
     RECT  11.477 24.96 11.909 24.984 ;
     RECT  11.801 10.08 11.945 13.08 ;
     RECT  11.909 7.152 12.125 7.416 ;
     RECT  11.369 20.64 12.125 21.528 ;
     RECT  12.125 21.504 12.197 21.528 ;
     RECT  10.901 22.8 12.409 23.4 ;
     RECT  12.409 22.8 12.517 23.688 ;
     RECT  12.509 21.696 12.524 21.72 ;
     RECT  12.517 22.8 12.524 24.504 ;
     RECT  11.411 16.656 12.613 17.4 ;
     RECT  12.481 13.344 12.661 13.368 ;
     RECT  11.873 14.736 12.661 15.048 ;
     RECT  12.524 21.696 13.045 24.504 ;
     RECT  12.625 25.68 13.045 25.704 ;
     RECT  11.795 5.04 13.057 5.688 ;
     RECT  12.613 16.656 13.057 18.216 ;
     RECT  13.057 16.56 13.093 18.216 ;
     RECT  11.441 19.632 13.093 19.656 ;
     RECT  11.801 8.496 13.165 9.096 ;
     RECT  11.945 10.08 13.165 11.736 ;
     RECT  11.693 3.072 13.208 3.144 ;
     RECT  13.057 5.04 13.208 6.024 ;
     RECT  12.125 7.344 13.208 7.416 ;
     RECT  13.165 8.496 13.208 11.736 ;
     RECT  12.661 13.344 13.208 15.048 ;
     RECT  13.093 16.56 13.208 19.656 ;
     RECT  13.045 21.696 13.208 25.704 ;
     RECT  13.208 2.148 13.312 25.932 ;
     RECT  13.312 2.418 13.504 25.662 ;
     RECT  13.504 23.04 14.033 23.4 ;
     RECT  14.033 23.04 14.105 23.352 ;
     RECT  13.504 3.312 14.243 6.12 ;
     RECT  13.504 7.344 14.339 7.752 ;
     RECT  14.105 23.232 14.393 23.352 ;
     RECT  13.504 21.936 14.465 22.056 ;
     RECT  13.504 20.304 14.533 20.328 ;
     RECT  14.243 4.992 14.753 6.12 ;
     RECT  14.339 7.728 14.753 7.752 ;
     RECT  13.504 13.728 14.821 13.752 ;
     RECT  13.504 14.736 14.821 15.048 ;
     RECT  13.504 16.272 14.821 17.928 ;
     RECT  14.533 19.824 14.821 20.328 ;
     RECT  14.821 13.728 14.867 20.328 ;
     RECT  14.867 18.672 14.908 20.328 ;
     RECT  13.504 9.072 14.917 12.744 ;
     RECT  14.867 13.728 14.917 15.72 ;
     RECT  14.243 3.312 15.037 3.96 ;
     RECT  14.465 21.936 15.109 21.96 ;
     RECT  14.908 19.392 15.157 20.328 ;
     RECT  15.109 21.36 15.157 21.96 ;
     RECT  14.753 5.04 15.781 6.12 ;
     RECT  15.037 3.12 15.908 3.96 ;
     RECT  15.781 5.04 15.908 6.36 ;
     RECT  15.781 7.392 15.908 7.416 ;
     RECT  14.917 9.072 15.908 15.72 ;
     RECT  14.867 17.088 15.908 17.64 ;
     RECT  15.157 19.392 15.908 21.96 ;
     RECT  14.393 23.328 15.908 23.352 ;
     RECT  13.504 25.536 15.908 25.56 ;
     RECT  15.908 2.148 16.012 25.932 ;
     RECT  16.012 2.418 16.204 25.662 ;
     RECT  17.629 4.32 18.684 4.344 ;
     RECT  17.629 6.048 18.684 6.072 ;
     RECT  17.629 7.776 18.684 7.8 ;
     RECT  17.629 9.504 18.684 9.528 ;
     RECT  17.629 11.232 18.684 11.256 ;
     RECT  17.629 12.96 18.684 12.984 ;
     RECT  17.629 14.688 18.684 14.712 ;
     RECT  16.204 16.416 18.684 16.44 ;
     RECT  16.204 18.144 18.684 18.168 ;
     RECT  17.629 19.872 18.684 19.896 ;
     RECT  16.204 21.6 18.684 21.624 ;
    LAYER M5 ;
     RECT  4.704 0.08 4.728 0.611 ;
     RECT  11.568 0.08 11.592 0.611 ;
     RECT  2.4 2.137 2.52 2.151 ;
     RECT  5.1 2.137 5.22 2.151 ;
     RECT  7.8 2.137 7.92 2.151 ;
     RECT  10.5 2.137 10.62 2.151 ;
     RECT  13.2 2.137 13.32 2.151 ;
     RECT  15.9 2.137 16.02 2.151 ;
     RECT  2.4 2.151 2.712 2.245 ;
     RECT  10.5 2.151 10.812 2.773 ;
     RECT  7.8 2.151 8.112 2.869 ;
     RECT  2.4 2.245 3.432 2.915 ;
     RECT  15.9 2.151 16.212 3.109 ;
     RECT  7.8 2.869 8.232 3.443 ;
     RECT  13.2 2.151 13.512 3.925 ;
     RECT  2.4 2.915 2.712 4.165 ;
     RECT  2.304 4.165 2.712 4.741 ;
     RECT  5.1 2.151 5.412 5.029 ;
     RECT  6.48 4.501 6.504 5.171 ;
     RECT  0.24 5.461 0.264 5.603 ;
     RECT  7.8 3.443 8.112 5.653 ;
     RECT  9.408 0.08 9.432 5.653 ;
     RECT  13.2 3.925 14.232 5.653 ;
     RECT  10.5 2.773 11.496 5.749 ;
     RECT  4.512 5.029 5.412 6.131 ;
     RECT  4.896 6.131 5.412 7.093 ;
     RECT  7.8 5.653 9.432 7.093 ;
     RECT  10.5 5.749 11.784 7.093 ;
     RECT  6.768 5.461 6.792 7.139 ;
     RECT  7.8 7.093 11.784 7.427 ;
     RECT  2.304 4.741 2.808 7.475 ;
     RECT  7.8 7.427 9.432 7.667 ;
     RECT  13.2 5.653 14.328 7.763 ;
     RECT  2.4 7.475 2.808 7.957 ;
     RECT  7.8 7.667 8.112 8.245 ;
     RECT  4.896 7.093 5.544 8.485 ;
     RECT  9.408 7.667 9.432 8.485 ;
     RECT  10.5 7.427 11.784 8.485 ;
     RECT  13.2 7.763 13.512 8.485 ;
     RECT  4.896 8.485 6.36 8.867 ;
     RECT  5.1 8.867 6.36 9.251 ;
     RECT  15.792 3.109 16.212 9.299 ;
     RECT  7.44 8.245 8.112 9.349 ;
     RECT  2.4 7.957 3.432 9.683 ;
     RECT  15.9 9.299 16.212 10.693 ;
     RECT  2.4 9.683 2.712 10.885 ;
     RECT  15.168 10.693 16.212 11.365 ;
     RECT  5.1 9.251 6.312 11.411 ;
     RECT  2.4 10.885 3.624 12.227 ;
     RECT  2.4 12.227 3.432 13.139 ;
     RECT  7.44 9.349 8.232 13.139 ;
     RECT  5.1 11.411 5.412 13.429 ;
     RECT  9.408 8.485 13.512 13.715 ;
     RECT  5.1 13.429 5.64 14.197 ;
     RECT  7.44 13.139 8.112 14.197 ;
     RECT  9.696 13.715 13.512 14.243 ;
     RECT  14.928 11.365 16.212 14.485 ;
     RECT  12.768 14.243 13.512 14.867 ;
     RECT  9.696 14.243 11.784 15.683 ;
     RECT  14.832 14.485 16.212 15.731 ;
     RECT  2.4 13.139 2.712 16.549 ;
     RECT  5.1 14.197 8.112 16.597 ;
     RECT  13.2 14.867 13.512 16.885 ;
     RECT  9.696 15.683 11.736 17.075 ;
     RECT  5.1 16.597 8.712 17.509 ;
     RECT  4.896 17.509 8.712 18.181 ;
     RECT  9.696 17.075 10.812 18.181 ;
     RECT  13.104 16.885 13.512 18.181 ;
     RECT  4.896 18.181 10.812 18.325 ;
     RECT  14.832 15.731 14.856 18.707 ;
     RECT  4.896 18.325 11.4 19.427 ;
     RECT  9.696 19.427 11.4 19.475 ;
     RECT  2.4 16.549 2.856 19.619 ;
     RECT  12.624 18.181 13.512 19.621 ;
     RECT  9.696 19.475 10.812 19.907 ;
     RECT  5.1 19.427 8.712 20.147 ;
     RECT  15.9 15.731 16.212 20.725 ;
     RECT  10.5 19.907 10.812 21.493 ;
     RECT  12.528 19.621 13.512 21.731 ;
     RECT  15.168 20.725 16.212 21.971 ;
     RECT  12.576 21.731 13.512 22.835 ;
     RECT  5.1 20.147 8.112 23.363 ;
     RECT  6.528 23.363 8.112 23.411 ;
     RECT  12.816 22.835 13.512 23.411 ;
     RECT  6.624 23.411 6.648 24.563 ;
     RECT  13.056 23.411 13.512 25.715 ;
     RECT  10.368 21.493 10.812 25.763 ;
     RECT  2.4 19.619 2.712 25.929 ;
     RECT  5.1 23.363 5.412 25.929 ;
     RECT  7.8 23.411 8.112 25.929 ;
     RECT  10.5 25.763 10.812 25.929 ;
     RECT  13.2 25.715 13.512 25.929 ;
     RECT  15.9 21.971 16.212 25.929 ;
     RECT  2.4 25.929 2.52 25.943 ;
     RECT  5.1 25.929 5.22 25.943 ;
     RECT  7.8 25.929 7.92 25.943 ;
     RECT  10.5 25.929 10.62 25.943 ;
     RECT  13.2 25.929 13.32 25.943 ;
     RECT  15.9 25.929 16.02 25.943 ;
  END
END qkd_d2d_cal_seq_pin
END LIBRARY
